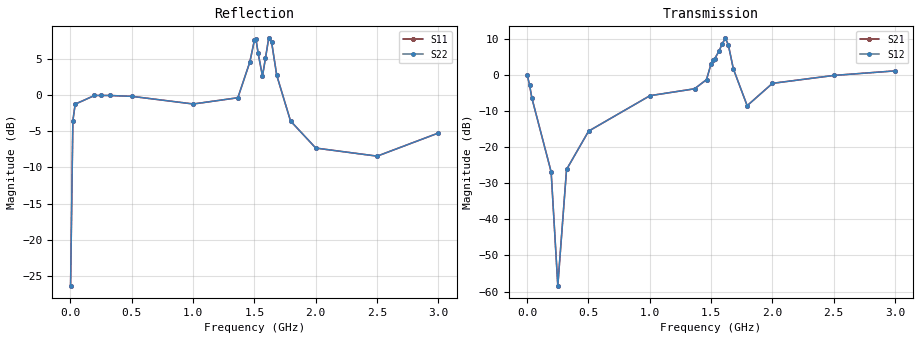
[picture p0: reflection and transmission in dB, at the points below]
!s-Parameter Generated by FASTRON Sdn. Bhd.
!FASTRON P/N : MICC-R82X
!Keysight Technologies,E4991B,MY54100416,A.01.15
!Date: Fri Aug 21 11:01:17 2026
!Version  : Rev00 Fri Aug 21 11:01:17 2026
!Data & Calibration Information:
!PortZ  Port1:50+j0  Port2:50+j0
!When reading, reference impedance value at option line is always used.
!Remarks : This data is being provided solely for informational purposes.
!Freq	S11	S21	S12	S22
# Hz S dB R 50
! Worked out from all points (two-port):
!   1601 points, 1 MHz to 3 GHz, reference 50 ohm
!   highest |S21| = 10.15 dB at 1.617 GHz (marker M1); lowest = -58.4 dB at 250.3 MHz (marker M2)
!   |S21| within 3 dB of the highest: 1.575 GHz to 1.649 GHz (73.55 MHz wide, 4.56 % of centre)
!   lowest |S11| = -26.4 dB at 1 MHz (marker M3), VSWR 1.10, Z = 50.4 + j4.8 ohm
!   |S11| at or under -10 dB: start of sweep to 7.255 MHz
!   |S22| runs from -26.4 to 8.0 dB; largest |S21 - S12| = 0
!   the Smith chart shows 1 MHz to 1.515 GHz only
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1000000  -26.39 82.0  -0.05 -2.7  -0.05 -2.7  -26.39 82.0
1.974375e7  -3.50 46.8  -2.74 -41.9  -2.74 -41.9  -3.50 46.8
3.84875e7  -1.22 28.8  -6.35 -60.3  -6.35 -60.3  -1.22 28.8
1.95935e8  -0.02 2.6  -26.83 -85.8  -26.83 -85.8  -0.02 2.6
2.502919e8  -0.01 0.0  -58.37 -8.7  -58.37 -8.7  -0.01 0.0
3.215181e8  -0.02 -2.8  -26.18 85.7  -26.18 85.7  -0.02 -2.8
5.014581e8  -0.14 -9.6  -15.55 79.8  -15.55 79.8  -0.14 -9.6
1.001916e9  -1.20 -31.1  -5.73 60.5  -5.73 60.5  -1.20 -31.1
1.365545e9  -0.33 -38.3  -3.82 67.7  -3.82 67.7  -0.33 -38.3
1.463012e9  4.62 -22.1  -1.29 132.1  -1.29 132.1  4.62 -22.1
1.5005e9  7.66 7.5  3.11 -167.3  3.11 -167.3  7.66 7.5
1.513621e9  7.78 26.6  4.18 -137.4  4.18 -137.4  7.78 26.6
1.53049e9  5.85 59.3  4.54 -90.0  4.54 -90.0  5.85 59.3
1.566103e9  2.67 131.2  6.67 -28.3  6.67 -28.3  2.67 131.2
1.59047e9  5.15 146.4  8.63 -21.8  8.63 -21.8  5.15 146.4
1.616711e9  7.90 130.1  10.15 -36.2  10.15 -36.2  7.90 130.1
1.641078e9  7.33 95.5  8.36 -62.2  8.36 -62.2  7.33 95.5
1.682314e9  2.79 58.8  1.67 -76.4  1.67 -76.4  2.79 58.8
1.794777e9  -3.55 11.9  -8.50 -21.4  -8.50 -21.4  -3.55 11.9
2.000958e9  -7.31 -46.0  -2.31 23.9  -2.31 23.9  -7.31 -46.0
2.501416e9  -8.43 -77.0  -0.12 22.0  -0.12 22.0  -8.43 -77.0
3e9  -5.23 -90.1  1.14 28.7  1.14 28.7  -5.23 -90.1
